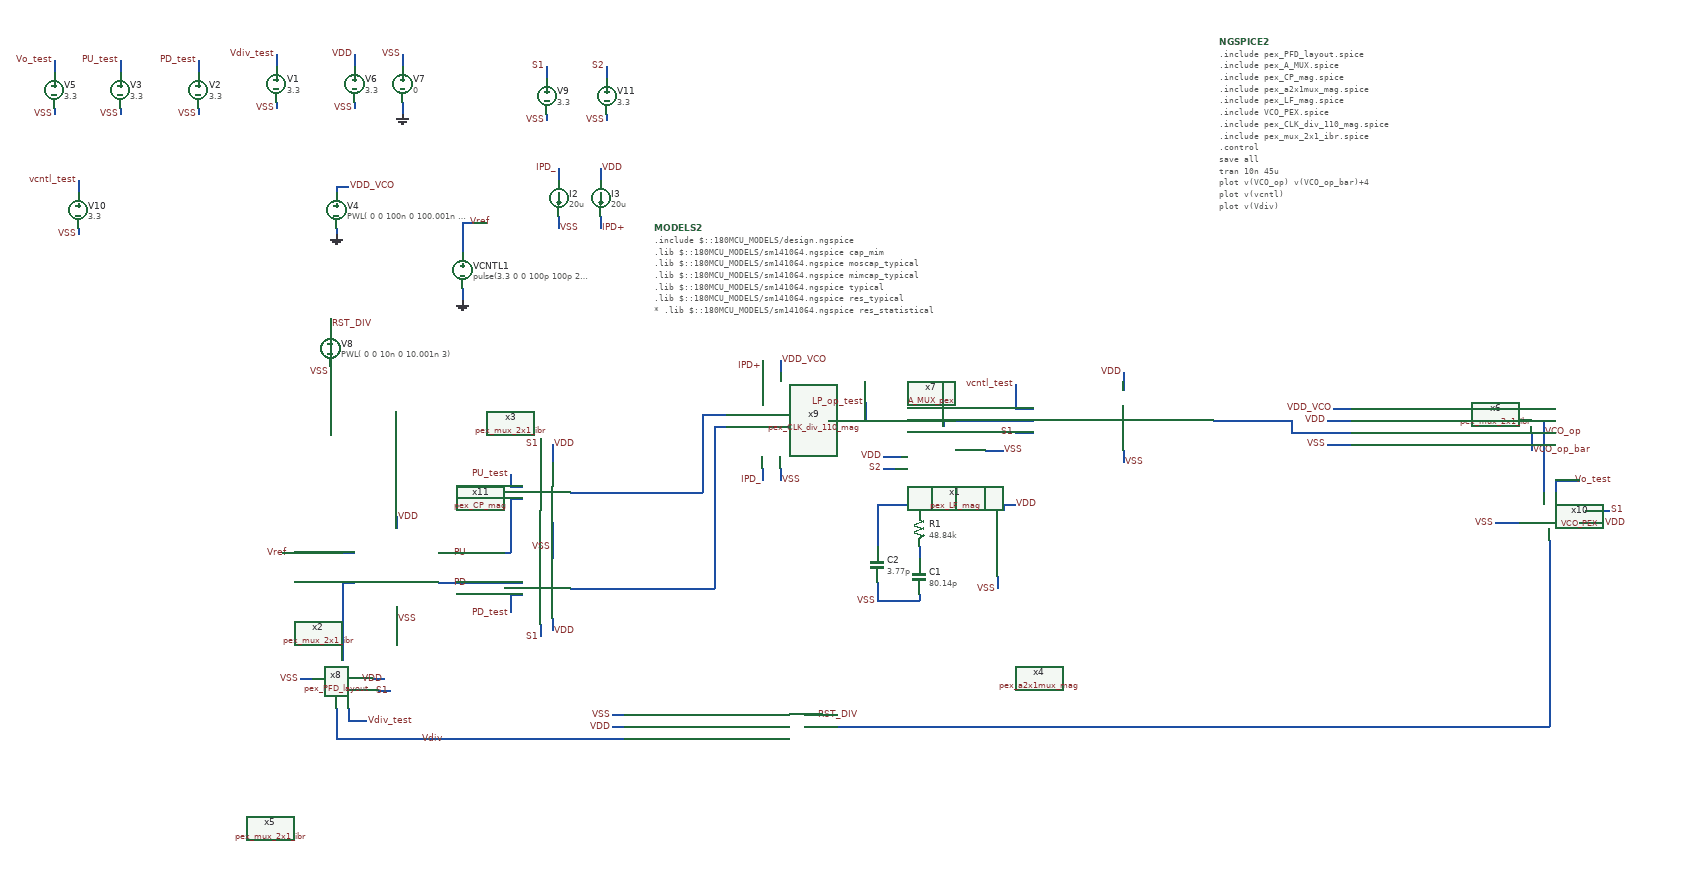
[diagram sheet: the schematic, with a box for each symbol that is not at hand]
v {xschem version=3.1.0 file_version=1.2
}
G {}
K {}
V {}
S {}
E {}
N 290 -470 290 -450 {
lab=VDD}
N 290 -320 290 -300 {
lab=VSS}
N 200 -410 220 -410 {
lab=Vref}
N 200 -360 220 -360 {
lab=#net1}
N 360 -360 380 -360 {
lab=PD}
N 120 -410 180 -410 {
lab=Vref}
N 180 -410 200 -410 {
lab=Vref}
N 380 -410 470 -410 {
lab=PU}
N 380 -360 470 -360 {
lab=PD}
N 200 -360 200 -230 {
lab=#net1}
N 210 -100 500 -100 {
lab=Vdiv}
N 200 -100 210 -100 {
lab=Vdiv}
N 360 -410 380 -410 {
lab=PU}
N 400 -850 400 -830 {
lab=GND}
N 190 -950 190 -940 {
lab=GND}
N 400 -960 420 -960 {
lab=Vref}
N 220 -1160 220 -1150 {
lab=VSS}
N 220 -1240 220 -1220 {
lab=VDD}
N 300 -1240 300 -1220 {
lab=VSS}
N 300 -1160 300 -1140 {
lab=GND}
N 500 -100 670 -100 {
lab=Vdiv}
N 1000 -120 1650 -120 {
lab=#net2}
N 180 -720 180 -710 {
lab=VSS}
N 180 -800 180 -780 {
lab=RST_DIV}
N 2200 -610 2200 -590 {
lab=VCO_op}
N 400 -960 400 -910 {
lab=Vref}
N 970 -120 990 -120 {
lab=#net2}
N 990 -120 1000 -120 {
lab=#net2}
N 190 -1020 190 -1010 {
lab=VDD_VCO}
N 190 -1020 210 -1020 {
lab=VDD_VCO}
N 540 -1140 540 -1130 {
lab=VSS}
N 540 -1220 540 -1200 {
lab=S1}
N 640 -1140 640 -1130 {
lab=VSS}
N 640 -1220 640 -1200 {
lab=S2}
N 930 -730 930 -710 {
lab=VDD_VCO}
N 930 -550 930 -530 {
lab=VSS}
N 820 -640 840 -640 {
lab=#net3}
N 900 -730 900 -710 {
lab=IPD+}
N 900 -550 900 -530 {
lab=IPD_}
N 560 -970 560 -950 {
lab=VSS}
N 630 -970 630 -950 {
lab=IPD+}
N 560 -1050 560 -1030 {
lab=IPD_}
N 630 -1050 630 -1030 {
lab=VDD}
N 100 -410 130 -410 {
lab=Vref}
N 2200 -630 2200 -610 {
lab=VCO_op}
N 2180 -630 2200 -630 {
lab=VCO_op}
N 2180 -610 2180 -580 {
lab=VCO_op_bar}
N 660 -120 670 -120 {
lab=VDD}
N 650 -120 660 -120 {
lab=VDD}
N 650 -140 670 -140 {
lab=VSS}
N 970 -140 1000 -140 {
lab=RST_DIV}
N 1850 -650 1880 -650 {
lab=VDD_VCO}
N 1290 -370 1290 -350 {
lab=VSS}
N 1300 -490 1300 -480 {
lab=VDD}
N 1300 -490 1320 -490 {
lab=VDD}
N 1100 -550 1120 -550 {
lab=S2}
N 1100 -570 1120 -570 {
lab=VDD}
N 1270 -580 1300 -580 {
lab=VSS}
N 1090 -360 1090 -330 {
lab=VSS}
N 1090 -330 1160 -330 {
lab=VSS}
N 1090 -490 1090 -420 {
lab=#net4}
N 1090 -490 1160 -490 {
lab=#net4}
N 1160 -490 1160 -480 {
lab=#net4}
N 1120 -570 1130 -570 {
lab=VDD}
N 1080 -630 1260 -630 {
lab=LP_op_test}
N 1160 -420 1160 -400 {
lab=#net5}
N 1160 -340 1160 -330 {
lab=VSS}
N 1160 -490 1180 -490 {
lab=#net4}
N 1180 -520 1180 -490 {
lab=#net4}
N 1270 -490 1270 -480 {
lab=#net6}
N 1220 -490 1270 -490 {
lab=#net6}
N 1220 -520 1220 -490 {
lab=#net6}
N 1200 -630 1200 -620 {
lab=LP_op_test}
N 1010 -630 1080 -630 {
lab=LP_op_test}
N 550 -460 550 -400 {
lab=VSS}
N 480 -500 500 -500 {
lab=PU}
N 480 -500 480 -410 {
lab=PU}
N 470 -410 480 -410 {
lab=PU}
N 530 -600 530 -570 {
lab=S1}
N 480 -520 500 -520 {
lab=PU_test}
N 480 -540 480 -520 {
lab=PU_test}
N 480 -340 500 -340 {
lab=PD_test}
N 480 -340 480 -310 {
lab=PD_test}
N 470 -360 500 -360 {
lab=PD}
N 580 -350 650 -350 {
lab=#net7}
N 830 -620 840 -620 {
lab=#net7}
N 580 -510 630 -510 {
lab=#net3}
N 810 -640 820 -640 {
lab=#net3}
N 550 -590 550 -560 {
lab=VDD}
N 550 -300 550 -280 {
lab=VDD}
N 530 -290 530 -270 {
lab=S1}
N 650 -350 820 -350 {
lab=#net7}
N 820 -620 820 -350 {
lab=#net7}
N 820 -620 830 -620 {
lab=#net7}
N 800 -640 810 -640 {
lab=#net3}
N 800 -640 800 -510 {
lab=#net3}
N 630 -510 800 -510 {
lab=#net3}
N 1650 -120 1940 -120 {
lab=#net2}
N 210 -150 210 -130 {
lab=Vdiv_test}
N 210 -130 240 -130 {
lab=Vdiv_test}
N 190 -150 190 -120 {
lab=Vdiv}
N 250 -200 270 -200 {
lab=VDD}
N 260 -180 280 -180 {
lab=S1}
N 190 -100 200 -100 {
lab=Vdiv}
N 190 -120 190 -100 {
lab=Vdiv}
N 130 -200 150 -200 {
lab=VSS}
N 90 -1160 90 -1150 {
lab=VSS}
N 90 -1240 90 -1220 {
lab=Vdiv_test}
N -40 -1150 -40 -1140 {
lab=VSS}
N -40 -1230 -40 -1210 {
lab=PD_test}
N -170 -1150 -170 -1140 {
lab=VSS}
N -170 -1230 -170 -1210 {
lab=PU_test}
N 2200 -590 2200 -510 {
lab=VCO_op}
N 2270 -480 2310 -480 {
lab=S1}
N 2220 -530 2220 -510 {
lab=Vo_test}
N 2220 -530 2260 -530 {
lab=Vo_test}
N 2260 -460 2300 -460 {
lab=VDD}
N 2120 -460 2160 -460 {
lab=VSS}
N 1260 -630 1350 -630 {
lab=LP_op_test}
N 1320 -650 1350 -650 {
lab=vcntl_test}
N 1320 -690 1320 -650 {
lab=vcntl_test}
N 1320 -610 1350 -610 {
lab=S1}
N 1650 -630 1780 -630 {
lab=#net8}
N 1500 -710 1500 -680 {
lab=VDD}
N 1500 -580 1500 -560 {
lab=VSS}
N 1940 -120 2200 -120 {
lab=#net2}
N 1780 -630 1780 -610 {
lab=#net8}
N 1780 -610 1880 -610 {
lab=#net8}
N 1840 -590 1880 -590 {
lab=VSS}
N 1840 -630 1880 -630 {
lab=VDD}
N 2210 -430 2210 -250 {
lab=#net2}
N 2210 -250 2210 -120 {
lab=#net2}
N 2200 -120 2210 -120 {
lab=#net2}
N 1070 -660 1070 -630 {
lab=LP_op_test}
N -280 -1150 -280 -1140 {
lab=VSS}
N -280 -1230 -280 -1210 {
lab=Vo_test}
N -240 -950 -240 -940 {
lab=VSS}
N -240 -1030 -240 -1010 {
lab=vcntl_test}
C {devices/lab_pin.sym} 290 -470 2 0 {name=p22 sig_type=std_logic lab=VDD}
C {devices/lab_wire.sym} 290 -300 2 0 {name=p23 sig_type=std_logic lab=VSS}
C {devices/lab_pin.sym} 370 -100 3 0 {name=p25 sig_type=std_logic lab=Vdiv
}
C {devices/lab_pin.sym} 2200 -610 2 0 {name=p26 sig_type=std_logic lab=VCO_op
}
C {devices/vsource.sym} 400 -880 0 0 {name=VCNTL1 value="pulse(3.3 0 0 100p 100p 250n 500n)"}
C {devices/gnd.sym} 400 -830 0 0 {name=l4 lab=GND}
C {devices/gnd.sym} 190 -940 0 0 {name=l5 lab=GND}
C {devices/vsource.sym} 190 -980 0 0 {name=V4 value=" PWL( 0 0 100n 0 100.001n 3.3)"}
C {devices/code_shown.sym} 1660 -1260 0 1 {name=NGSPICE2 only_toplevel=true
value="
.include "pex_PFD_layout.spice"
.include "pex_A_MUX.spice"
.include "pex_CP_mag.spice"
.include "pex_a2x1mux_mag.spice"
.include "pex_LF_mag.spice"
.include "VCO_PEX.spice"
.include "pex_CLK_div_110_mag.spice"
.include "pex_mux_2x1_ibr.spice"
.control
save all
tran 10n 45u 
plot v(VCO_op) v(VCO_op_bar)+4
plot v(vcntl)
plot v(Vdiv)
plot v(vref)
**write pll_4.raw
.endc
"}
C {devices/vsource.sym} 220 -1190 0 0 {name=V6 value=3.3}
C {devices/vsource.sym} 300 -1190 0 0 {name=V7 value=0}
C {devices/lab_wire.sym} 300 -1240 0 0 {name=p27 sig_type=std_logic lab=VSS}
C {devices/lab_wire.sym} 220 -1150 0 0 {name=p29 sig_type=std_logic lab=VSS
}
C {devices/lab_wire.sym} 220 -1240 0 0 {name=p30 sig_type=std_logic lab=VDD}
C {devices/gnd.sym} 300 -1140 0 0 {name=l6 lab=GND}
C {devices/lab_pin.sym} 2180 -580 2 0 {name=p31 sig_type=std_logic lab=VCO_op_bar
}
C {devices/lab_pin.sym} 210 -1020 2 0 {name=p32 sig_type=std_logic lab=VDD_VCO}
C {devices/lab_pin.sym} 410 -960 2 0 {name=p33 sig_type=std_logic lab=Vref
}
C {devices/lab_wire.sym} 180 -710 0 0 {name=p34 sig_type=std_logic lab=VSS
}
C {devices/vsource.sym} 180 -750 0 0 {name=V8 value=" PWL( 0 0 10n 0 10.001n 3)"}
C {devices/lab_pin.sym} 410 -410 1 0 {name=p37 sig_type=std_logic lab=PU}
C {devices/lab_pin.sym} 410 -360 1 0 {name=p40 sig_type=std_logic lab=PD}
C {devices/vsource.sym} 540 -1170 0 0 {name=V9 value=3.3}
C {devices/lab_wire.sym} 540 -1130 0 0 {name=p41 sig_type=std_logic lab=VSS
}
C {devices/lab_wire.sym} 540 -1220 0 0 {name=p42 sig_type=std_logic lab=S1}
C {devices/vsource.sym} 640 -1170 0 0 {name=V11 value=3.3}
C {devices/lab_wire.sym} 640 -1130 0 0 {name=p45 sig_type=std_logic lab=VSS
}
C {devices/lab_wire.sym} 640 -1220 0 0 {name=p46 sig_type=std_logic lab=S2}
C {devices/lab_pin.sym} 180 -790 2 0 {name=p67 sig_type=std_logic lab=RST_DIV}
C {devices/lab_wire.sym} 930 -530 2 0 {name=p68 sig_type=std_logic lab=VSS}
C {devices/lab_wire.sym} 900 -720 0 0 {name=p70 sig_type=std_logic lab=IPD+}
C {devices/lab_wire.sym} 900 -530 0 0 {name=p71 sig_type=std_logic lab=IPD_}
C {devices/isource.sym} 560 -1000 0 0 {name=I2 value=20u}
C {devices/isource.sym} 630 -1000 0 0 {name=I3 value=20u}
C {devices/lab_wire.sym} 560 -1050 0 0 {name=p72 sig_type=std_logic lab=IPD_}
C {devices/lab_wire.sym} 630 -950 2 0 {name=p73 sig_type=std_logic lab=IPD+}
C {devices/lab_wire.sym} 560 -950 2 0 {name=p74 sig_type=std_logic lab=VSS}
C {devices/lab_wire.sym} 630 -1050 2 0 {name=p75 sig_type=std_logic lab=VDD}
C {devices/lab_pin.sym} 110 -410 0 0 {name=p76 sig_type=std_logic lab=Vref
}
C {devices/code_shown.sym} 720 -950 0 0 {name=MODELS2 only_toplevel=true
format="tcleval( @value )"
value="
.include $::180MCU_MODELS/design.ngspice
.lib $::180MCU_MODELS/sm141064.ngspice cap_mim
.lib $::180MCU_MODELS/sm141064.ngspice moscap_typical
.lib $::180MCU_MODELS/sm141064.ngspice mimcap_typical
.lib $::180MCU_MODELS/sm141064.ngspice typical
.lib $::180MCU_MODELS/sm141064.ngspice res_typical
* .lib $::180MCU_MODELS/sm141064.ngspice res_statistical
"}
C {devices/lab_wire.sym} 650 -140 0 0 {name=p78 sig_type=std_logic lab=VSS}
C {devices/lab_pin.sym} 650 -120 0 0 {name=p79 sig_type=std_logic lab=VDD}
C {devices/lab_pin.sym} 990 -140 2 0 {name=p80 sig_type=std_logic lab=RST_DIV}
C {pex_CLK_div_110_mag.sym} 820 -120 0 1 {name=x9}
C {pex_CP_mag.sym} 350 -430 0 0 {name=x11}
C {devices/lab_pin.sym} 930 -730 2 0 {name=p81 sig_type=std_logic lab=VDD_VCO}
C {devices/lab_pin.sym} 1850 -650 0 0 {name=p89 sig_type=std_logic lab=VDD_VCO}
C {devices/lab_wire.sym} 1290 -350 2 1 {name=p5 sig_type=std_logic lab=VSS}
C {devices/lab_wire.sym} 1320 -490 0 1 {name=p21 sig_type=std_logic lab=VDD}
C {devices/lab_wire.sym} 1300 -580 2 0 {name=p6 sig_type=std_logic lab=VSS}
C {devices/lab_wire.sym} 1100 -570 2 1 {name=p1 sig_type=std_logic lab=VDD}
C {devices/lab_wire.sym} 1100 -550 1 1 {name=p2 sig_type=std_logic lab=S2}
C {devices/capa.sym} 1160 -370 0 0 {name=C1
m=1
value=80.14p
footprint=1206
device="ceramic capacitor"}
C {devices/capa.sym} 1090 -390 0 0 {name=C2
m=1
value=3.77p
footprint=1206
device="ceramic capacitor"}
C {devices/res.sym} 1160 -450 0 0 {name=R1
value=48.84k
footprint=1206
device=resistor
m=1}
C {devices/lab_wire.sym} 1090 -330 2 1 {name=p3 sig_type=std_logic lab=VSS}
C {pex_a2x1mux_mag.sym} 1360 -200 3 0 {name=x4}
C {pex_LF_mag.sym} 1430 -320 0 1 {name=x1}
C {pex_mux_2x1_ibr.sym} 300 -390 0 0 {name=x2}
C {pex_mux_2x1_ibr.sym} 300 -470 2 1 {name=x3}
C {devices/lab_wire.sym} 550 -420 0 0 {name=p4 sig_type=std_logic lab=VSS
}
C {devices/lab_wire.sym} 550 -590 2 0 {name=p7 sig_type=std_logic lab=VDD}
C {devices/lab_wire.sym} 550 -280 2 0 {name=p8 sig_type=std_logic lab=VDD}
C {devices/lab_wire.sym} 530 -590 0 0 {name=p10 sig_type=std_logic lab=S1}
C {devices/lab_wire.sym} 530 -270 0 0 {name=p9 sig_type=std_logic lab=S1}
C {devices/lab_pin.sym} 480 -540 0 0 {name=p11 sig_type=std_logic lab=PU_test}
C {devices/lab_pin.sym} 480 -310 0 0 {name=p12 sig_type=std_logic lab=PD_test}
C {pex_mux_2x1_ibr.sym} 80 50 1 1 {name=x5}
C {devices/lab_wire.sym} 130 -200 3 0 {name=p13 sig_type=std_logic lab=VSS
}
C {devices/lab_wire.sym} 270 -200 1 0 {name=p14 sig_type=std_logic lab=VDD}
C {devices/lab_wire.sym} 280 -180 3 0 {name=p15 sig_type=std_logic lab=S1}
C {devices/lab_pin.sym} 240 -130 2 0 {name=p16 sig_type=std_logic lab=Vdiv_test}
C {devices/vsource.sym} 90 -1190 0 0 {name=V1 value=3.3}
C {devices/lab_wire.sym} 90 -1150 0 0 {name=p17 sig_type=std_logic lab=VSS
}
C {devices/lab_wire.sym} 90 -1240 0 0 {name=p18 sig_type=std_logic lab=Vdiv_test}
C {devices/vsource.sym} -40 -1180 0 0 {name=V2 value=3.3}
C {devices/lab_wire.sym} -40 -1140 0 0 {name=p19 sig_type=std_logic lab=VSS
}
C {devices/lab_wire.sym} -40 -1230 0 0 {name=p24 sig_type=std_logic lab=PD_test}
C {devices/vsource.sym} -170 -1180 0 0 {name=V3 value=3.3}
C {devices/lab_wire.sym} -170 -1140 0 0 {name=p28 sig_type=std_logic lab=VSS
}
C {devices/lab_wire.sym} -170 -1230 0 0 {name=p35 sig_type=std_logic lab=PU_test}
C {devices/lab_wire.sym} 2310 -480 0 1 {name=p36 sig_type=std_logic lab=S1}
C {devices/lab_wire.sym} 2300 -460 0 1 {name=p38 sig_type=std_logic lab=VDD}
C {devices/lab_wire.sym} 2120 -460 0 0 {name=p39 sig_type=std_logic lab=VSS}
C {devices/lab_pin.sym} 2250 -530 2 0 {name=p47 sig_type=std_logic lab=Vo_test
}
C {A_MUX_pex.sym} 1500 -630 0 0 {name=x7}
C {devices/lab_wire.sym} 1320 -610 2 1 {name=p48 sig_type=std_logic lab=S1}
C {devices/lab_wire.sym} 1320 -690 1 0 {name=p49 sig_type=std_logic lab=vcntl_test}
C {devices/lab_wire.sym} 1500 -710 2 1 {name=p50 sig_type=std_logic lab=VDD}
C {devices/lab_wire.sym} 1500 -560 2 0 {name=p51 sig_type=std_logic lab=VSS}
C {devices/lab_wire.sym} 1840 -590 3 0 {name=p52 sig_type=std_logic lab=VSS}
C {devices/lab_wire.sym} 1840 -630 2 1 {name=p53 sig_type=std_logic lab=VDD}
C {pex_mux_2x1_ibr.sym} 2090 -710 1 0 {name=x6}
C {devices/lab_wire.sym} 1070 -660 1 0 {name=p20 sig_type=std_logic lab=LP_op_test}
C {pex_PFD_layout.sym} 0 -200 0 0 {name=x8}
C {VCO_PEX.sym} 2030 -620 0 0 {name=x10}
C {devices/vsource.sym} -280 -1180 0 0 {name=V5 value=3.3}
C {devices/lab_wire.sym} -280 -1140 0 0 {name=p43 sig_type=std_logic lab=VSS
}
C {devices/lab_wire.sym} -280 -1230 0 0 {name=p44 sig_type=std_logic lab=Vo_test}
C {devices/vsource.sym} -240 -980 0 0 {name=V10 value=3.3}
C {devices/lab_wire.sym} -240 -940 0 0 {name=p54 sig_type=std_logic lab=VSS
}
C {devices/lab_wire.sym} -240 -1030 0 0 {name=p55 sig_type=std_logic lab=vcntl_test}
